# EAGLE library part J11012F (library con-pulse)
PULSEJACK (TM) 1x1 Tab-UP RJ45 10/100 Base-TX RJ45 1x1 Tab-UP with LEDs 8-pin (J1 series) and 6-pin (JP series) integrated magnetics connector, designed to support applications, such as ADSL modems, LAN-on-Motherboard, and Hub and Switches. Source: www.pulseeng.com .. PulseJack-J402.pdf

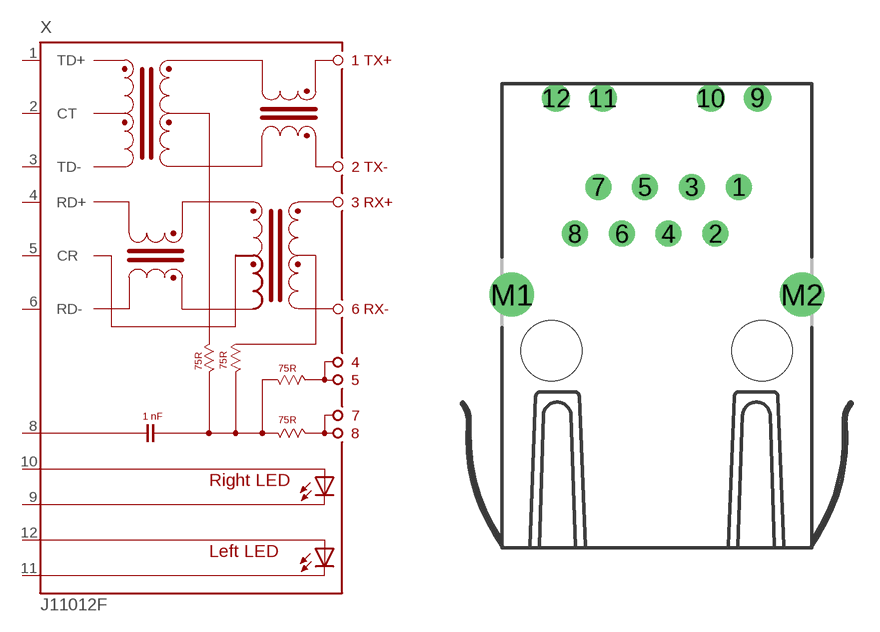
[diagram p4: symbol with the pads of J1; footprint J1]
Designator prefix X

## J11012F01C (OC_FARNELL: unknown; OC_NEWARK: unknown), J11012F21C (OC_FARNELL: unknown; OC_NEWARK: unknown), J11012F21K (OC_FARNELL: unknown; OC_NEWARK: unknown)  [J1]
1  TD+  in
2  CT  in
3  TD-  in
4  RD+  in
5  CR  in
6  RD-  in
8  8  in
9  C-R  pas
10  A-R  pas
11  C-L  pas
12  A-L  pas

## Footprint J1 (pad centres in mm)
PULSEJACK (TM) 1x1 Tab-UP RJ45 10/100 Base-TX RJ45 1x1 Tab-UP with LEDs 8-pin (J1 series) and 6-pin (JP series) integrated magnetics connector, designed to support applications, such as ADSL modems,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
drill 0.9 pad 1.3 round: 1 4.445,2.54; 2 3.175,0; 3 1.905,2.54; 4 0.635,0; 5 -0.635,2.54; 6 -1.905,0; 7 -3.175,2.54; 8 -4.445,0
drill 1 pad 1.422 round: 9 5.465,7.37; 10 2.925,7.37; 11 -2.925,7.37; 12 -5.465,7.37
drill 1.6 pad 2.184 round: M1 -7.875,-3.3; M2 7.875,-3.3
hole 3.3 at 5.715,-6.35
hole 3.3 at -5.715,-6.35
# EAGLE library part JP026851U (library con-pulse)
PULSEJACK (TM) 1x1 Tab-UP RJ45 10/100 Base-TX RJ45 1x1 Tab-UP with LEDs 8-pin (J1 series) and 6-pin (JP series) integrated magnetics connector, designed to support applications, such as ADSL modems, LAN-on-Motherboard, and Hub and Switches. Source: www.pulseeng.com .. PulseJack-J402.pdf

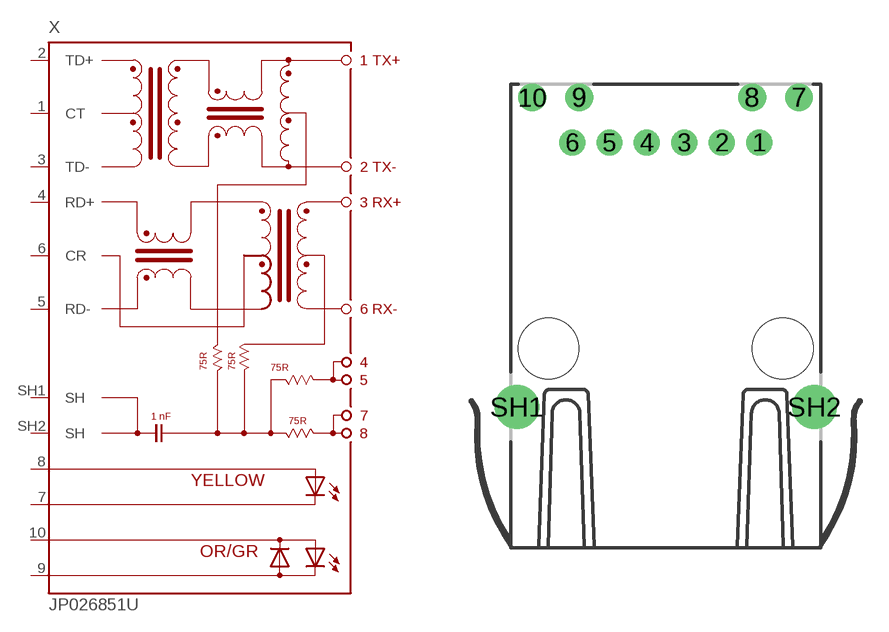
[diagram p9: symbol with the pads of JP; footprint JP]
Designator prefix X

## JP026851U (OC_FARNELL: unknown; OC_NEWARK: unknown)  [JP]
1  CT  in
2  TD+  in
3  TD-  in
4  RD+  in
5  RD-  in
6  CR  in
7  CY  pas
8  AY  pas
9  COG  pas
10  AOG  pas
SH1  SH  in
SH2  SH  in

## Footprint JP (pad centres in mm)
PULSEJACK (TM) 1x1 Tab-UP RJ45 10/100 Base-TX RJ45 1x1 Tab-UP with LEDs 8-pin (J1 series) and 6-pin (JP series) integrated magnetics connector, designed to support applications, such as ADSL modems,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
drill 0.9 pad 1.3 round: 1 5.075,11.18; 2 3.045,11.18; 3 1.015,11.18; 4 -1.015,11.18; 5 -3.045,11.18; 6 -5.075,11.18
drill 1 pad 1.4 round: 7 7.23,13.62; 8 4.69,13.62; 9 -4.69,13.62; 10 -7.23,13.62
drill 1.6 pad 2.184 round: SH1 -8.065,-3.17; SH2 8.065,-3.17
hole 3.3 at 6.35,0
hole 3.3 at -6.35,0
